VERSION 5.8 ;
BUSBITCHARS "[]" ;
DIVIDERCHAR "/" ;
UNITS
    DATABASE MICRONS 2000 ;
END UNITS

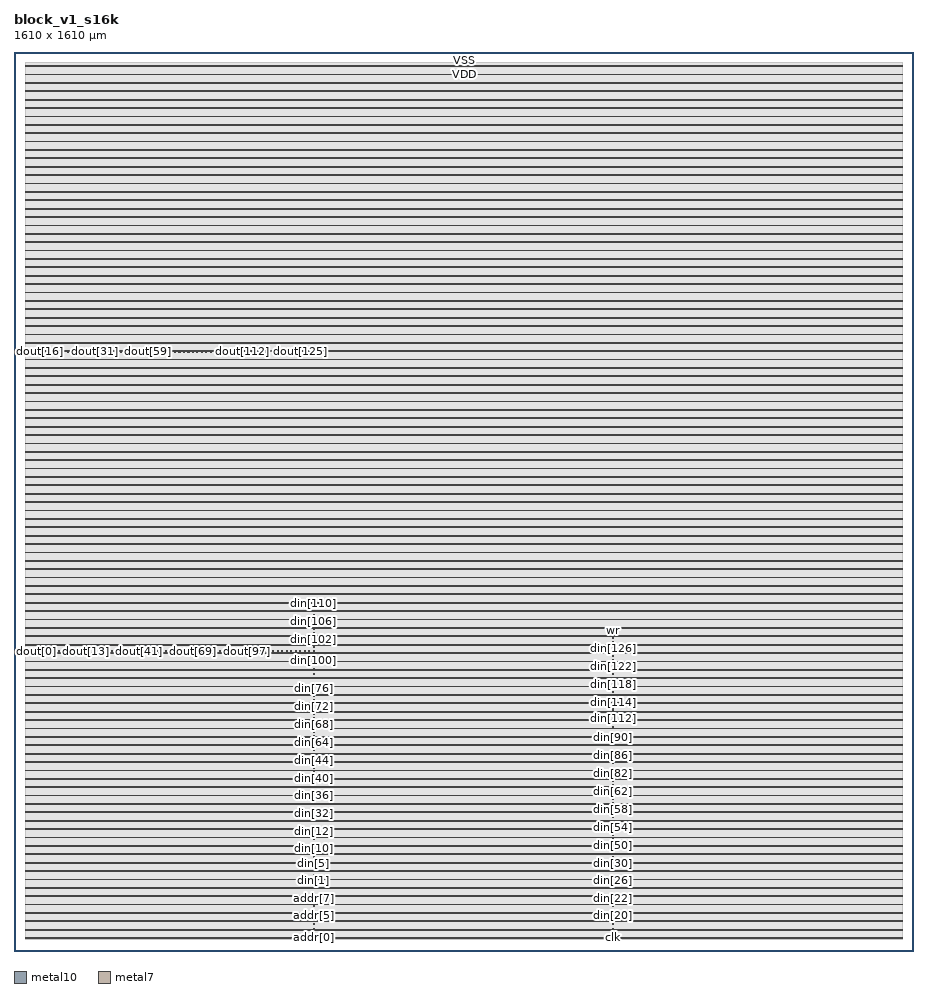
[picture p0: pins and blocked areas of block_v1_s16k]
MACRO block_v1_s16k
  FOREIGN block_v1_s16k 0 0 ;
  CLASS BLOCK ;
  SIZE 1610 BY 1610 ;
  PIN addr[0]
    DIRECTION INPUT ;
    USE SIGNAL ;
    PORT
      LAYER metal10 ;
        RECT  535.095 23.07 537.095 25.07 ;
    END
  END addr[0]
  PIN addr[1]
    DIRECTION INPUT ;
    USE SIGNAL ;
    PORT
      LAYER metal10 ;
        RECT  535.095 31.07 537.095 33.07 ;
    END
  END addr[1]
  PIN addr[2]
    DIRECTION INPUT ;
    USE SIGNAL ;
    PORT
      LAYER metal10 ;
        RECT  535.095 39.07 537.095 41.07 ;
    END
  END addr[2]
  PIN addr[3]
    DIRECTION INPUT ;
    USE SIGNAL ;
    PORT
      LAYER metal10 ;
        RECT  535.095 47.07 537.095 49.07 ;
    END
  END addr[3]
  PIN addr[4]
    DIRECTION INPUT ;
    USE SIGNAL ;
    PORT
      LAYER metal10 ;
        RECT  535.095 55.07 537.095 57.07 ;
    END
  END addr[4]
  PIN addr[5]
    DIRECTION INPUT ;
    USE SIGNAL ;
    PORT
      LAYER metal10 ;
        RECT  535.095 63.07 537.095 65.07 ;
    END
  END addr[5]
  PIN addr[6]
    DIRECTION INPUT ;
    USE SIGNAL ;
    PORT
      LAYER metal10 ;
        RECT  535.095 71.07 537.095 73.07 ;
    END
  END addr[6]
  PIN addr[7]
    DIRECTION INPUT ;
    USE SIGNAL ;
    PORT
      LAYER metal10 ;
        RECT  535.095 79.07 537.095 81.07 ;
    END
  END addr[7]
  PIN addr[8]
    DIRECTION INPUT ;
    USE SIGNAL ;
    PORT
      LAYER metal10 ;
        RECT  535.095 87.07 537.095 89.07 ;
    END
  END addr[8]
  PIN addr[9]
    DIRECTION INPUT ;
    USE SIGNAL ;
    PORT
      LAYER metal10 ;
        RECT  535.095 95.07 537.095 97.07 ;
    END
  END addr[9]
  PIN clk
    DIRECTION INPUT ;
    USE SIGNAL ;
    PORT
      LAYER metal10 ;
        RECT  1071.095 23.07 1073.095 25.07 ;
    END
  END clk
  PIN din[0]
    DIRECTION INPUT ;
    USE SIGNAL ;
    PORT
      LAYER metal10 ;
        RECT  535.095 103.07 537.095 105.07 ;
    END
  END din[0]
  PIN din[100]
    DIRECTION INPUT ;
    USE SIGNAL ;
    PORT
      LAYER metal10 ;
        RECT  535.095 519.07 537.095 521.07 ;
    END
  END din[100]
  PIN din[101]
    DIRECTION INPUT ;
    USE SIGNAL ;
    PORT
      LAYER metal10 ;
        RECT  535.095 527.07 537.095 529.07 ;
    END
  END din[101]
  PIN din[102]
    DIRECTION INPUT ;
    USE SIGNAL ;
    PORT
      LAYER metal10 ;
        RECT  535.095 543.07 537.095 545.07 ;
    END
  END din[102]
  PIN din[103]
    DIRECTION INPUT ;
    USE SIGNAL ;
    PORT
      LAYER metal10 ;
        RECT  535.095 551.07 537.095 553.07 ;
    END
  END din[103]
  PIN din[104]
    DIRECTION INPUT ;
    USE SIGNAL ;
    PORT
      LAYER metal10 ;
        RECT  535.095 559.07 537.095 561.07 ;
    END
  END din[104]
  PIN din[105]
    DIRECTION INPUT ;
    USE SIGNAL ;
    PORT
      LAYER metal10 ;
        RECT  535.095 567.07 537.095 569.07 ;
    END
  END din[105]
  PIN din[106]
    DIRECTION INPUT ;
    USE SIGNAL ;
    PORT
      LAYER metal10 ;
        RECT  535.095 575.07 537.095 577.07 ;
    END
  END din[106]
  PIN din[107]
    DIRECTION INPUT ;
    USE SIGNAL ;
    PORT
      LAYER metal10 ;
        RECT  535.095 583.07 537.095 585.07 ;
    END
  END din[107]
  PIN din[108]
    DIRECTION INPUT ;
    USE SIGNAL ;
    PORT
      LAYER metal10 ;
        RECT  535.095 591.07 537.095 593.07 ;
    END
  END din[108]
  PIN din[109]
    DIRECTION INPUT ;
    USE SIGNAL ;
    PORT
      LAYER metal10 ;
        RECT  535.095 599.07 537.095 601.07 ;
    END
  END din[109]
  PIN din[10]
    DIRECTION INPUT ;
    USE SIGNAL ;
    PORT
      LAYER metal10 ;
        RECT  535.095 183.07 537.095 185.07 ;
    END
  END din[10]
  PIN din[110]
    DIRECTION INPUT ;
    USE SIGNAL ;
    PORT
      LAYER metal10 ;
        RECT  535.095 607.07 537.095 609.07 ;
    END
  END din[110]
  PIN din[111]
    DIRECTION INPUT ;
    USE SIGNAL ;
    PORT
      LAYER metal10 ;
        RECT  535.095 615.07 537.095 617.07 ;
    END
  END din[111]
  PIN din[112]
    DIRECTION INPUT ;
    USE SIGNAL ;
    PORT
      LAYER metal10 ;
        RECT  1071.095 415.07 1073.095 417.07 ;
    END
  END din[112]
  PIN din[113]
    DIRECTION INPUT ;
    USE SIGNAL ;
    PORT
      LAYER metal10 ;
        RECT  1071.095 423.07 1073.095 425.07 ;
    END
  END din[113]
  PIN din[114]
    DIRECTION INPUT ;
    USE SIGNAL ;
    PORT
      LAYER metal10 ;
        RECT  1071.095 431.07 1073.095 433.07 ;
    END
  END din[114]
  PIN din[115]
    DIRECTION INPUT ;
    USE SIGNAL ;
    PORT
      LAYER metal10 ;
        RECT  1071.095 439.07 1073.095 441.07 ;
    END
  END din[115]
  PIN din[116]
    DIRECTION INPUT ;
    USE SIGNAL ;
    PORT
      LAYER metal10 ;
        RECT  1071.095 447.07 1073.095 449.07 ;
    END
  END din[116]
  PIN din[117]
    DIRECTION INPUT ;
    USE SIGNAL ;
    PORT
      LAYER metal10 ;
        RECT  1071.095 455.07 1073.095 457.07 ;
    END
  END din[117]
  PIN din[118]
    DIRECTION INPUT ;
    USE SIGNAL ;
    PORT
      LAYER metal10 ;
        RECT  1071.095 463.07 1073.095 465.07 ;
    END
  END din[118]
  PIN din[119]
    DIRECTION INPUT ;
    USE SIGNAL ;
    PORT
      LAYER metal10 ;
        RECT  1071.095 471.07 1073.095 473.07 ;
    END
  END din[119]
  PIN din[11]
    DIRECTION INPUT ;
    USE SIGNAL ;
    PORT
      LAYER metal10 ;
        RECT  535.095 191.07 537.095 193.07 ;
    END
  END din[11]
  PIN din[120]
    DIRECTION INPUT ;
    USE SIGNAL ;
    PORT
      LAYER metal10 ;
        RECT  1071.095 479.07 1073.095 481.07 ;
    END
  END din[120]
  PIN din[121]
    DIRECTION INPUT ;
    USE SIGNAL ;
    PORT
      LAYER metal10 ;
        RECT  1071.095 487.07 1073.095 489.07 ;
    END
  END din[121]
  PIN din[122]
    DIRECTION INPUT ;
    USE SIGNAL ;
    PORT
      LAYER metal10 ;
        RECT  1071.095 495.07 1073.095 497.07 ;
    END
  END din[122]
  PIN din[123]
    DIRECTION INPUT ;
    USE SIGNAL ;
    PORT
      LAYER metal10 ;
        RECT  1071.095 503.07 1073.095 505.07 ;
    END
  END din[123]
  PIN din[124]
    DIRECTION INPUT ;
    USE SIGNAL ;
    PORT
      LAYER metal10 ;
        RECT  1071.095 511.07 1073.095 513.07 ;
    END
  END din[124]
  PIN din[125]
    DIRECTION INPUT ;
    USE SIGNAL ;
    PORT
      LAYER metal10 ;
        RECT  1071.095 519.07 1073.095 521.07 ;
    END
  END din[125]
  PIN din[126]
    DIRECTION INPUT ;
    USE SIGNAL ;
    PORT
      LAYER metal10 ;
        RECT  1071.095 527.07 1073.095 529.07 ;
    END
  END din[126]
  PIN din[127]
    DIRECTION INPUT ;
    USE SIGNAL ;
    PORT
      LAYER metal10 ;
        RECT  1071.095 543.07 1073.095 545.07 ;
    END
  END din[127]
  PIN din[12]
    DIRECTION INPUT ;
    USE SIGNAL ;
    PORT
      LAYER metal10 ;
        RECT  535.095 199.07 537.095 201.07 ;
    END
  END din[12]
  PIN din[13]
    DIRECTION INPUT ;
    USE SIGNAL ;
    PORT
      LAYER metal10 ;
        RECT  535.095 207.07 537.095 209.07 ;
    END
  END din[13]
  PIN din[14]
    DIRECTION INPUT ;
    USE SIGNAL ;
    PORT
      LAYER metal10 ;
        RECT  535.095 215.07 537.095 217.07 ;
    END
  END din[14]
  PIN din[15]
    DIRECTION INPUT ;
    USE SIGNAL ;
    PORT
      LAYER metal10 ;
        RECT  535.095 223.07 537.095 225.07 ;
    END
  END din[15]
  PIN din[16]
    DIRECTION INPUT ;
    USE SIGNAL ;
    PORT
      LAYER metal10 ;
        RECT  1071.095 31.07 1073.095 33.07 ;
    END
  END din[16]
  PIN din[17]
    DIRECTION INPUT ;
    USE SIGNAL ;
    PORT
      LAYER metal10 ;
        RECT  1071.095 39.07 1073.095 41.07 ;
    END
  END din[17]
  PIN din[18]
    DIRECTION INPUT ;
    USE SIGNAL ;
    PORT
      LAYER metal10 ;
        RECT  1071.095 47.07 1073.095 49.07 ;
    END
  END din[18]
  PIN din[19]
    DIRECTION INPUT ;
    USE SIGNAL ;
    PORT
      LAYER metal10 ;
        RECT  1071.095 55.07 1073.095 57.07 ;
    END
  END din[19]
  PIN din[1]
    DIRECTION INPUT ;
    USE SIGNAL ;
    PORT
      LAYER metal10 ;
        RECT  535.095 111.07 537.095 113.07 ;
    END
  END din[1]
  PIN din[20]
    DIRECTION INPUT ;
    USE SIGNAL ;
    PORT
      LAYER metal10 ;
        RECT  1071.095 63.07 1073.095 65.07 ;
    END
  END din[20]
  PIN din[21]
    DIRECTION INPUT ;
    USE SIGNAL ;
    PORT
      LAYER metal10 ;
        RECT  1071.095 71.07 1073.095 73.07 ;
    END
  END din[21]
  PIN din[22]
    DIRECTION INPUT ;
    USE SIGNAL ;
    PORT
      LAYER metal10 ;
        RECT  1071.095 79.07 1073.095 81.07 ;
    END
  END din[22]
  PIN din[23]
    DIRECTION INPUT ;
    USE SIGNAL ;
    PORT
      LAYER metal10 ;
        RECT  1071.095 87.07 1073.095 89.07 ;
    END
  END din[23]
  PIN din[24]
    DIRECTION INPUT ;
    USE SIGNAL ;
    PORT
      LAYER metal10 ;
        RECT  1071.095 95.07 1073.095 97.07 ;
    END
  END din[24]
  PIN din[25]
    DIRECTION INPUT ;
    USE SIGNAL ;
    PORT
      LAYER metal10 ;
        RECT  1071.095 103.07 1073.095 105.07 ;
    END
  END din[25]
  PIN din[26]
    DIRECTION INPUT ;
    USE SIGNAL ;
    PORT
      LAYER metal10 ;
        RECT  1071.095 111.07 1073.095 113.07 ;
    END
  END din[26]
  PIN din[27]
    DIRECTION INPUT ;
    USE SIGNAL ;
    PORT
      LAYER metal10 ;
        RECT  1071.095 119.07 1073.095 121.07 ;
    END
  END din[27]
  PIN din[28]
    DIRECTION INPUT ;
    USE SIGNAL ;
    PORT
      LAYER metal10 ;
        RECT  1071.095 127.07 1073.095 129.07 ;
    END
  END din[28]
  PIN din[29]
    DIRECTION INPUT ;
    USE SIGNAL ;
    PORT
      LAYER metal10 ;
        RECT  1071.095 135.07 1073.095 137.07 ;
    END
  END din[29]
  PIN din[2]
    DIRECTION INPUT ;
    USE SIGNAL ;
    PORT
      LAYER metal10 ;
        RECT  535.095 119.07 537.095 121.07 ;
    END
  END din[2]
  PIN din[30]
    DIRECTION INPUT ;
    USE SIGNAL ;
    PORT
      LAYER metal10 ;
        RECT  1071.095 143.07 1073.095 145.07 ;
    END
  END din[30]
  PIN din[31]
    DIRECTION INPUT ;
    USE SIGNAL ;
    PORT
      LAYER metal10 ;
        RECT  1071.095 151.07 1073.095 153.07 ;
    END
  END din[31]
  PIN din[32]
    DIRECTION INPUT ;
    USE SIGNAL ;
    PORT
      LAYER metal10 ;
        RECT  535.095 231.07 537.095 233.07 ;
    END
  END din[32]
  PIN din[33]
    DIRECTION INPUT ;
    USE SIGNAL ;
    PORT
      LAYER metal10 ;
        RECT  535.095 239.07 537.095 241.07 ;
    END
  END din[33]
  PIN din[34]
    DIRECTION INPUT ;
    USE SIGNAL ;
    PORT
      LAYER metal10 ;
        RECT  535.095 247.07 537.095 249.07 ;
    END
  END din[34]
  PIN din[35]
    DIRECTION INPUT ;
    USE SIGNAL ;
    PORT
      LAYER metal10 ;
        RECT  535.095 255.07 537.095 257.07 ;
    END
  END din[35]
  PIN din[36]
    DIRECTION INPUT ;
    USE SIGNAL ;
    PORT
      LAYER metal10 ;
        RECT  535.095 263.07 537.095 265.07 ;
    END
  END din[36]
  PIN din[37]
    DIRECTION INPUT ;
    USE SIGNAL ;
    PORT
      LAYER metal10 ;
        RECT  535.095 271.07 537.095 273.07 ;
    END
  END din[37]
  PIN din[38]
    DIRECTION INPUT ;
    USE SIGNAL ;
    PORT
      LAYER metal10 ;
        RECT  535.095 279.07 537.095 281.07 ;
    END
  END din[38]
  PIN din[39]
    DIRECTION INPUT ;
    USE SIGNAL ;
    PORT
      LAYER metal10 ;
        RECT  535.095 287.07 537.095 289.07 ;
    END
  END din[39]
  PIN din[3]
    DIRECTION INPUT ;
    USE SIGNAL ;
    PORT
      LAYER metal10 ;
        RECT  535.095 127.07 537.095 129.07 ;
    END
  END din[3]
  PIN din[40]
    DIRECTION INPUT ;
    USE SIGNAL ;
    PORT
      LAYER metal10 ;
        RECT  535.095 295.07 537.095 297.07 ;
    END
  END din[40]
  PIN din[41]
    DIRECTION INPUT ;
    USE SIGNAL ;
    PORT
      LAYER metal10 ;
        RECT  535.095 303.07 537.095 305.07 ;
    END
  END din[41]
  PIN din[42]
    DIRECTION INPUT ;
    USE SIGNAL ;
    PORT
      LAYER metal10 ;
        RECT  535.095 311.07 537.095 313.07 ;
    END
  END din[42]
  PIN din[43]
    DIRECTION INPUT ;
    USE SIGNAL ;
    PORT
      LAYER metal10 ;
        RECT  535.095 319.07 537.095 321.07 ;
    END
  END din[43]
  PIN din[44]
    DIRECTION INPUT ;
    USE SIGNAL ;
    PORT
      LAYER metal10 ;
        RECT  535.095 327.07 537.095 329.07 ;
    END
  END din[44]
  PIN din[45]
    DIRECTION INPUT ;
    USE SIGNAL ;
    PORT
      LAYER metal10 ;
        RECT  535.095 335.07 537.095 337.07 ;
    END
  END din[45]
  PIN din[46]
    DIRECTION INPUT ;
    USE SIGNAL ;
    PORT
      LAYER metal10 ;
        RECT  535.095 343.07 537.095 345.07 ;
    END
  END din[46]
  PIN din[47]
    DIRECTION INPUT ;
    USE SIGNAL ;
    PORT
      LAYER metal10 ;
        RECT  535.095 351.07 537.095 353.07 ;
    END
  END din[47]
  PIN din[48]
    DIRECTION INPUT ;
    USE SIGNAL ;
    PORT
      LAYER metal10 ;
        RECT  1071.095 159.07 1073.095 161.07 ;
    END
  END din[48]
  PIN din[49]
    DIRECTION INPUT ;
    USE SIGNAL ;
    PORT
      LAYER metal10 ;
        RECT  1071.095 167.07 1073.095 169.07 ;
    END
  END din[49]
  PIN din[4]
    DIRECTION INPUT ;
    USE SIGNAL ;
    PORT
      LAYER metal10 ;
        RECT  535.095 135.07 537.095 137.07 ;
    END
  END din[4]
  PIN din[50]
    DIRECTION INPUT ;
    USE SIGNAL ;
    PORT
      LAYER metal10 ;
        RECT  1071.095 175.07 1073.095 177.07 ;
    END
  END din[50]
  PIN din[51]
    DIRECTION INPUT ;
    USE SIGNAL ;
    PORT
      LAYER metal10 ;
        RECT  1071.095 183.07 1073.095 185.07 ;
    END
  END din[51]
  PIN din[52]
    DIRECTION INPUT ;
    USE SIGNAL ;
    PORT
      LAYER metal10 ;
        RECT  1071.095 191.07 1073.095 193.07 ;
    END
  END din[52]
  PIN din[53]
    DIRECTION INPUT ;
    USE SIGNAL ;
    PORT
      LAYER metal10 ;
        RECT  1071.095 199.07 1073.095 201.07 ;
    END
  END din[53]
  PIN din[54]
    DIRECTION INPUT ;
    USE SIGNAL ;
    PORT
      LAYER metal10 ;
        RECT  1071.095 207.07 1073.095 209.07 ;
    END
  END din[54]
  PIN din[55]
    DIRECTION INPUT ;
    USE SIGNAL ;
    PORT
      LAYER metal10 ;
        RECT  1071.095 215.07 1073.095 217.07 ;
    END
  END din[55]
  PIN din[56]
    DIRECTION INPUT ;
    USE SIGNAL ;
    PORT
      LAYER metal10 ;
        RECT  1071.095 223.07 1073.095 225.07 ;
    END
  END din[56]
  PIN din[57]
    DIRECTION INPUT ;
    USE SIGNAL ;
    PORT
      LAYER metal10 ;
        RECT  1071.095 231.07 1073.095 233.07 ;
    END
  END din[57]
  PIN din[58]
    DIRECTION INPUT ;
    USE SIGNAL ;
    PORT
      LAYER metal10 ;
        RECT  1071.095 239.07 1073.095 241.07 ;
    END
  END din[58]
  PIN din[59]
    DIRECTION INPUT ;
    USE SIGNAL ;
    PORT
      LAYER metal10 ;
        RECT  1071.095 247.07 1073.095 249.07 ;
    END
  END din[59]
  PIN din[5]
    DIRECTION INPUT ;
    USE SIGNAL ;
    PORT
      LAYER metal10 ;
        RECT  535.095 143.07 537.095 145.07 ;
    END
  END din[5]
  PIN din[60]
    DIRECTION INPUT ;
    USE SIGNAL ;
    PORT
      LAYER metal10 ;
        RECT  1071.095 255.07 1073.095 257.07 ;
    END
  END din[60]
  PIN din[61]
    DIRECTION INPUT ;
    USE SIGNAL ;
    PORT
      LAYER metal10 ;
        RECT  1071.095 263.07 1073.095 265.07 ;
    END
  END din[61]
  PIN din[62]
    DIRECTION INPUT ;
    USE SIGNAL ;
    PORT
      LAYER metal10 ;
        RECT  1071.095 271.07 1073.095 273.07 ;
    END
  END din[62]
  PIN din[63]
    DIRECTION INPUT ;
    USE SIGNAL ;
    PORT
      LAYER metal10 ;
        RECT  1071.095 279.07 1073.095 281.07 ;
    END
  END din[63]
  PIN din[64]
    DIRECTION INPUT ;
    USE SIGNAL ;
    PORT
      LAYER metal10 ;
        RECT  535.095 359.07 537.095 361.07 ;
    END
  END din[64]
  PIN din[65]
    DIRECTION INPUT ;
    USE SIGNAL ;
    PORT
      LAYER metal10 ;
        RECT  535.095 367.07 537.095 369.07 ;
    END
  END din[65]
  PIN din[66]
    DIRECTION INPUT ;
    USE SIGNAL ;
    PORT
      LAYER metal10 ;
        RECT  535.095 375.07 537.095 377.07 ;
    END
  END din[66]
  PIN din[67]
    DIRECTION INPUT ;
    USE SIGNAL ;
    PORT
      LAYER metal10 ;
        RECT  535.095 383.07 537.095 385.07 ;
    END
  END din[67]
  PIN din[68]
    DIRECTION INPUT ;
    USE SIGNAL ;
    PORT
      LAYER metal10 ;
        RECT  535.095 391.07 537.095 393.07 ;
    END
  END din[68]
  PIN din[69]
    DIRECTION INPUT ;
    USE SIGNAL ;
    PORT
      LAYER metal10 ;
        RECT  535.095 399.07 537.095 401.07 ;
    END
  END din[69]
  PIN din[6]
    DIRECTION INPUT ;
    USE SIGNAL ;
    PORT
      LAYER metal10 ;
        RECT  535.095 151.07 537.095 153.07 ;
    END
  END din[6]
  PIN din[70]
    DIRECTION INPUT ;
    USE SIGNAL ;
    PORT
      LAYER metal10 ;
        RECT  535.095 407.07 537.095 409.07 ;
    END
  END din[70]
  PIN din[71]
    DIRECTION INPUT ;
    USE SIGNAL ;
    PORT
      LAYER metal10 ;
        RECT  535.095 415.07 537.095 417.07 ;
    END
  END din[71]
  PIN din[72]
    DIRECTION INPUT ;
    USE SIGNAL ;
    PORT
      LAYER metal10 ;
        RECT  535.095 423.07 537.095 425.07 ;
    END
  END din[72]
  PIN din[73]
    DIRECTION INPUT ;
    USE SIGNAL ;
    PORT
      LAYER metal10 ;
        RECT  535.095 431.07 537.095 433.07 ;
    END
  END din[73]
  PIN din[74]
    DIRECTION INPUT ;
    USE SIGNAL ;
    PORT
      LAYER metal10 ;
        RECT  535.095 439.07 537.095 441.07 ;
    END
  END din[74]
  PIN din[75]
    DIRECTION INPUT ;
    USE SIGNAL ;
    PORT
      LAYER metal10 ;
        RECT  535.095 447.07 537.095 449.07 ;
    END
  END din[75]
  PIN din[76]
    DIRECTION INPUT ;
    USE SIGNAL ;
    PORT
      LAYER metal10 ;
        RECT  535.095 455.07 537.095 457.07 ;
    END
  END din[76]
  PIN din[77]
    DIRECTION INPUT ;
    USE SIGNAL ;
    PORT
      LAYER metal10 ;
        RECT  535.095 463.07 537.095 465.07 ;
    END
  END din[77]
  PIN din[78]
    DIRECTION INPUT ;
    USE SIGNAL ;
    PORT
      LAYER metal10 ;
        RECT  535.095 471.07 537.095 473.07 ;
    END
  END din[78]
  PIN din[79]
    DIRECTION INPUT ;
    USE SIGNAL ;
    PORT
      LAYER metal10 ;
        RECT  535.095 479.07 537.095 481.07 ;
    END
  END din[79]
  PIN din[7]
    DIRECTION INPUT ;
    USE SIGNAL ;
    PORT
      LAYER metal10 ;
        RECT  535.095 159.07 537.095 161.07 ;
    END
  END din[7]
  PIN din[80]
    DIRECTION INPUT ;
    USE SIGNAL ;
    PORT
      LAYER metal10 ;
        RECT  1071.095 287.07 1073.095 289.07 ;
    END
  END din[80]
  PIN din[81]
    DIRECTION INPUT ;
    USE SIGNAL ;
    PORT
      LAYER metal10 ;
        RECT  1071.095 295.07 1073.095 297.07 ;
    END
  END din[81]
  PIN din[82]
    DIRECTION INPUT ;
    USE SIGNAL ;
    PORT
      LAYER metal10 ;
        RECT  1071.095 303.07 1073.095 305.07 ;
    END
  END din[82]
  PIN din[83]
    DIRECTION INPUT ;
    USE SIGNAL ;
    PORT
      LAYER metal10 ;
        RECT  1071.095 311.07 1073.095 313.07 ;
    END
  END din[83]
  PIN din[84]
    DIRECTION INPUT ;
    USE SIGNAL ;
    PORT
      LAYER metal10 ;
        RECT  1071.095 319.07 1073.095 321.07 ;
    END
  END din[84]
  PIN din[85]
    DIRECTION INPUT ;
    USE SIGNAL ;
    PORT
      LAYER metal10 ;
        RECT  1071.095 327.07 1073.095 329.07 ;
    END
  END din[85]
  PIN din[86]
    DIRECTION INPUT ;
    USE SIGNAL ;
    PORT
      LAYER metal10 ;
        RECT  1071.095 335.07 1073.095 337.07 ;
    END
  END din[86]
  PIN din[87]
    DIRECTION INPUT ;
    USE SIGNAL ;
    PORT
      LAYER metal10 ;
        RECT  1071.095 343.07 1073.095 345.07 ;
    END
  END din[87]
  PIN din[88]
    DIRECTION INPUT ;
    USE SIGNAL ;
    PORT
      LAYER metal10 ;
        RECT  1071.095 351.07 1073.095 353.07 ;
    END
  END din[88]
  PIN din[89]
    DIRECTION INPUT ;
    USE SIGNAL ;
    PORT
      LAYER metal10 ;
        RECT  1071.095 359.07 1073.095 361.07 ;
    END
  END din[89]
  PIN din[8]
    DIRECTION INPUT ;
    USE SIGNAL ;
    PORT
      LAYER metal10 ;
        RECT  535.095 167.07 537.095 169.07 ;
    END
  END din[8]
  PIN din[90]
    DIRECTION INPUT ;
    USE SIGNAL ;
    PORT
      LAYER metal10 ;
        RECT  1071.095 367.07 1073.095 369.07 ;
    END
  END din[90]
  PIN din[91]
    DIRECTION INPUT ;
    USE SIGNAL ;
    PORT
      LAYER metal10 ;
        RECT  1071.095 375.07 1073.095 377.07 ;
    END
  END din[91]
  PIN din[92]
    DIRECTION INPUT ;
    USE SIGNAL ;
    PORT
      LAYER metal10 ;
        RECT  1071.095 383.07 1073.095 385.07 ;
    END
  END din[92]
  PIN din[93]
    DIRECTION INPUT ;
    USE SIGNAL ;
    PORT
      LAYER metal10 ;
        RECT  1071.095 391.07 1073.095 393.07 ;
    END
  END din[93]
  PIN din[94]
    DIRECTION INPUT ;
    USE SIGNAL ;
    PORT
      LAYER metal10 ;
        RECT  1071.095 399.07 1073.095 401.07 ;
    END
  END din[94]
  PIN din[95]
    DIRECTION INPUT ;
    USE SIGNAL ;
    PORT
      LAYER metal10 ;
        RECT  1071.095 407.07 1073.095 409.07 ;
    END
  END din[95]
  PIN din[96]
    DIRECTION INPUT ;
    USE SIGNAL ;
    PORT
      LAYER metal10 ;
        RECT  535.095 487.07 537.095 489.07 ;
    END
  END din[96]
  PIN din[97]
    DIRECTION INPUT ;
    USE SIGNAL ;
    PORT
      LAYER metal10 ;
        RECT  535.095 495.07 537.095 497.07 ;
    END
  END din[97]
  PIN din[98]
    DIRECTION INPUT ;
    USE SIGNAL ;
    PORT
      LAYER metal10 ;
        RECT  535.095 503.07 537.095 505.07 ;
    END
  END din[98]
  PIN din[99]
    DIRECTION INPUT ;
    USE SIGNAL ;
    PORT
      LAYER metal10 ;
        RECT  535.095 511.07 537.095 513.07 ;
    END
  END din[99]
  PIN din[9]
    DIRECTION INPUT ;
    USE SIGNAL ;
    PORT
      LAYER metal10 ;
        RECT  535.095 175.07 537.095 177.07 ;
    END
  END din[9]
  PIN dout[0]
    DIRECTION OUTPUT ;
    USE SIGNAL ;
    PORT
      LAYER metal10 ;
        RECT  23.095 535.07 25.095 537.07 ;
    END
  END dout[0]
  PIN dout[100]
    DIRECTION OUTPUT ;
    USE SIGNAL ;
    PORT
      LAYER metal10 ;
        RECT  439.095 535.07 441.095 537.07 ;
    END
  END dout[100]
  PIN dout[101]
    DIRECTION OUTPUT ;
    USE SIGNAL ;
    PORT
      LAYER metal10 ;
        RECT  447.095 535.07 449.095 537.07 ;
    END
  END dout[101]
  PIN dout[102]
    DIRECTION OUTPUT ;
    USE SIGNAL ;
    PORT
      LAYER metal10 ;
        RECT  455.095 535.07 457.095 537.07 ;
    END
  END dout[102]
  PIN dout[103]
    DIRECTION OUTPUT ;
    USE SIGNAL ;
    PORT
      LAYER metal10 ;
        RECT  463.095 535.07 465.095 537.07 ;
    END
  END dout[103]
  PIN dout[104]
    DIRECTION OUTPUT ;
    USE SIGNAL ;
    PORT
      LAYER metal10 ;
        RECT  471.095 535.07 473.095 537.07 ;
    END
  END dout[104]
  PIN dout[105]
    DIRECTION OUTPUT ;
    USE SIGNAL ;
    PORT
      LAYER metal10 ;
        RECT  479.095 535.07 481.095 537.07 ;
    END
  END dout[105]
  PIN dout[106]
    DIRECTION OUTPUT ;
    USE SIGNAL ;
    PORT
      LAYER metal10 ;
        RECT  487.095 535.07 489.095 537.07 ;
    END
  END dout[106]
  PIN dout[107]
    DIRECTION OUTPUT ;
    USE SIGNAL ;
    PORT
      LAYER metal10 ;
        RECT  495.095 535.07 497.095 537.07 ;
    END
  END dout[107]
  PIN dout[108]
    DIRECTION OUTPUT ;
    USE SIGNAL ;
    PORT
      LAYER metal10 ;
        RECT  503.095 535.07 505.095 537.07 ;
    END
  END dout[108]
  PIN dout[109]
    DIRECTION OUTPUT ;
    USE SIGNAL ;
    PORT
      LAYER metal10 ;
        RECT  511.095 535.07 513.095 537.07 ;
    END
  END dout[109]
  PIN dout[10]
    DIRECTION OUTPUT ;
    USE SIGNAL ;
    PORT
      LAYER metal10 ;
        RECT  103.095 535.07 105.095 537.07 ;
    END
  END dout[10]
  PIN dout[110]
    DIRECTION OUTPUT ;
    USE SIGNAL ;
    PORT
      LAYER metal10 ;
        RECT  519.095 535.07 521.095 537.07 ;
    END
  END dout[110]
  PIN dout[111]
    DIRECTION OUTPUT ;
    USE SIGNAL ;
    PORT
      LAYER metal10 ;
        RECT  527.095 535.07 529.095 537.07 ;
    END
  END dout[111]
  PIN dout[112]
    DIRECTION OUTPUT ;
    USE SIGNAL ;
    PORT
      LAYER metal10 ;
        RECT  407.095 1071.07 409.095 1073.07 ;
    END
  END dout[112]
  PIN dout[113]
    DIRECTION OUTPUT ;
    USE SIGNAL ;
    PORT
      LAYER metal10 ;
        RECT  415.095 1071.07 417.095 1073.07 ;
    END
  END dout[113]
  PIN dout[114]
    DIRECTION OUTPUT ;
    USE SIGNAL ;
    PORT
      LAYER metal10 ;
        RECT  423.095 1071.07 425.095 1073.07 ;
    END
  END dout[114]
  PIN dout[115]
    DIRECTION OUTPUT ;
    USE SIGNAL ;
    PORT
      LAYER metal10 ;
        RECT  431.095 1071.07 433.095 1073.07 ;
    END
  END dout[115]
  PIN dout[116]
    DIRECTION OUTPUT ;
    USE SIGNAL ;
    PORT
      LAYER metal10 ;
        RECT  439.095 1071.07 441.095 1073.07 ;
    END
  END dout[116]
  PIN dout[117]
    DIRECTION OUTPUT ;
    USE SIGNAL ;
    PORT
      LAYER metal10 ;
        RECT  447.095 1071.07 449.095 1073.07 ;
    END
  END dout[117]
  PIN dout[118]
    DIRECTION OUTPUT ;
    USE SIGNAL ;
    PORT
      LAYER metal10 ;
        RECT  455.095 1071.07 457.095 1073.07 ;
    END
  END dout[118]
  PIN dout[119]
    DIRECTION OUTPUT ;
    USE SIGNAL ;
    PORT
      LAYER metal10 ;
        RECT  463.095 1071.07 465.095 1073.07 ;
    END
  END dout[119]
  PIN dout[11]
    DIRECTION OUTPUT ;
    USE SIGNAL ;
    PORT
      LAYER metal10 ;
        RECT  111.095 535.07 113.095 537.07 ;
    END
  END dout[11]
  PIN dout[120]
    DIRECTION OUTPUT ;
    USE SIGNAL ;
    PORT
      LAYER metal10 ;
        RECT  471.095 1071.07 473.095 1073.07 ;
    END
  END dout[120]
  PIN dout[121]
    DIRECTION OUTPUT ;
    USE SIGNAL ;
    PORT
      LAYER metal10 ;
        RECT  479.095 1071.07 481.095 1073.07 ;
    END
  END dout[121]
  PIN dout[122]
    DIRECTION OUTPUT ;
    USE SIGNAL ;
    PORT
      LAYER metal10 ;
        RECT  487.095 1071.07 489.095 1073.07 ;
    END
  END dout[122]
  PIN dout[123]
    DIRECTION OUTPUT ;
    USE SIGNAL ;
    PORT
      LAYER metal10 ;
        RECT  495.095 1071.07 497.095 1073.07 ;
    END
  END dout[123]
  PIN dout[124]
    DIRECTION OUTPUT ;
    USE SIGNAL ;
    PORT
      LAYER metal10 ;
        RECT  503.095 1071.07 505.095 1073.07 ;
    END
  END dout[124]
  PIN dout[125]
    DIRECTION OUTPUT ;
    USE SIGNAL ;
    PORT
      LAYER metal10 ;
        RECT  511.095 1071.07 513.095 1073.07 ;
    END
  END dout[125]
  PIN dout[126]
    DIRECTION OUTPUT ;
    USE SIGNAL ;
    PORT
      LAYER metal10 ;
        RECT  519.095 1071.07 521.095 1073.07 ;
    END
  END dout[126]
  PIN dout[127]
    DIRECTION OUTPUT ;
    USE SIGNAL ;
    PORT
      LAYER metal10 ;
        RECT  527.095 1071.07 529.095 1073.07 ;
    END
  END dout[127]
  PIN dout[12]
    DIRECTION OUTPUT ;
    USE SIGNAL ;
    PORT
      LAYER metal10 ;
        RECT  119.095 535.07 121.095 537.07 ;
    END
  END dout[12]
  PIN dout[13]
    DIRECTION OUTPUT ;
    USE SIGNAL ;
    PORT
      LAYER metal10 ;
        RECT  127.095 535.07 129.095 537.07 ;
    END
  END dout[13]
  PIN dout[14]
    DIRECTION OUTPUT ;
    USE SIGNAL ;
    PORT
      LAYER metal10 ;
        RECT  135.095 535.07 137.095 537.07 ;
    END
  END dout[14]
  PIN dout[15]
    DIRECTION OUTPUT ;
    USE SIGNAL ;
    PORT
      LAYER metal10 ;
        RECT  143.095 535.07 145.095 537.07 ;
    END
  END dout[15]
  PIN dout[16]
    DIRECTION OUTPUT ;
    USE SIGNAL ;
    PORT
      LAYER metal10 ;
        RECT  23.095 1071.07 25.095 1073.07 ;
    END
  END dout[16]
  PIN dout[17]
    DIRECTION OUTPUT ;
    USE SIGNAL ;
    PORT
      LAYER metal10 ;
        RECT  31.095 1071.07 33.095 1073.07 ;
    END
  END dout[17]
  PIN dout[18]
    DIRECTION OUTPUT ;
    USE SIGNAL ;
    PORT
      LAYER metal10 ;
        RECT  39.095 1071.07 41.095 1073.07 ;
    END
  END dout[18]
  PIN dout[19]
    DIRECTION OUTPUT ;
    USE SIGNAL ;
    PORT
      LAYER metal10 ;
        RECT  47.095 1071.07 49.095 1073.07 ;
    END
  END dout[19]
  PIN dout[1]
    DIRECTION OUTPUT ;
    USE SIGNAL ;
    PORT
      LAYER metal10 ;
        RECT  31.095 535.07 33.095 537.07 ;
    END
  END dout[1]
  PIN dout[20]
    DIRECTION OUTPUT ;
    USE SIGNAL ;
    PORT
      LAYER metal10 ;
        RECT  55.095 1071.07 57.095 1073.07 ;
    END
  END dout[20]
  PIN dout[21]
    DIRECTION OUTPUT ;
    USE SIGNAL ;
    PORT
      LAYER metal10 ;
        RECT  63.095 1071.07 65.095 1073.07 ;
    END
  END dout[21]
  PIN dout[22]
    DIRECTION OUTPUT ;
    USE SIGNAL ;
    PORT
      LAYER metal10 ;
        RECT  71.095 1071.07 73.095 1073.07 ;
    END
  END dout[22]
  PIN dout[23]
    DIRECTION OUTPUT ;
    USE SIGNAL ;
    PORT
      LAYER metal10 ;
        RECT  79.095 1071.07 81.095 1073.07 ;
    END
  END dout[23]
  PIN dout[24]
    DIRECTION OUTPUT ;
    USE SIGNAL ;
    PORT
      LAYER metal10 ;
        RECT  87.095 1071.07 89.095 1073.07 ;
    END
  END dout[24]
  PIN dout[25]
    DIRECTION OUTPUT ;
    USE SIGNAL ;
    PORT
      LAYER metal10 ;
        RECT  95.095 1071.07 97.095 1073.07 ;
    END
  END dout[25]
  PIN dout[26]
    DIRECTION OUTPUT ;
    USE SIGNAL ;
    PORT
      LAYER metal10 ;
        RECT  103.095 1071.07 105.095 1073.07 ;
    END
  END dout[26]
  PIN dout[27]
    DIRECTION OUTPUT ;
    USE SIGNAL ;
    PORT
      LAYER metal10 ;
        RECT  111.095 1071.07 113.095 1073.07 ;
    END
  END dout[27]
  PIN dout[28]
    DIRECTION OUTPUT ;
    USE SIGNAL ;
    PORT
      LAYER metal10 ;
        RECT  119.095 1071.07 121.095 1073.07 ;
    END
  END dout[28]
  PIN dout[29]
    DIRECTION OUTPUT ;
    USE SIGNAL ;
    PORT
      LAYER metal10 ;
        RECT  127.095 1071.07 129.095 1073.07 ;
    END
  END dout[29]
  PIN dout[2]
    DIRECTION OUTPUT ;
    USE SIGNAL ;
    PORT
      LAYER metal10 ;
        RECT  39.095 535.07 41.095 537.07 ;
    END
  END dout[2]
  PIN dout[30]
    DIRECTION OUTPUT ;
    USE SIGNAL ;
    PORT
      LAYER metal10 ;
        RECT  135.095 1071.07 137.095 1073.07 ;
    END
  END dout[30]
  PIN dout[31]
    DIRECTION OUTPUT ;
    USE SIGNAL ;
    PORT
      LAYER metal10 ;
        RECT  143.095 1071.07 145.095 1073.07 ;
    END
  END dout[31]
  PIN dout[32]
    DIRECTION OUTPUT ;
    USE SIGNAL ;
    PORT
      LAYER metal10 ;
        RECT  151.095 535.07 153.095 537.07 ;
    END
  END dout[32]
  PIN dout[33]
    DIRECTION OUTPUT ;
    USE SIGNAL ;
    PORT
      LAYER metal10 ;
        RECT  159.095 535.07 161.095 537.07 ;
    END
  END dout[33]
  PIN dout[34]
    DIRECTION OUTPUT ;
    USE SIGNAL ;
    PORT
      LAYER metal10 ;
        RECT  167.095 535.07 169.095 537.07 ;
    END
  END dout[34]
  PIN dout[35]
    DIRECTION OUTPUT ;
    USE SIGNAL ;
    PORT
      LAYER metal10 ;
        RECT  175.095 535.07 177.095 537.07 ;
    END
  END dout[35]
  PIN dout[36]
    DIRECTION OUTPUT ;
    USE SIGNAL ;
    PORT
      LAYER metal10 ;
        RECT  183.095 535.07 185.095 537.07 ;
    END
  END dout[36]
  PIN dout[37]
    DIRECTION OUTPUT ;
    USE SIGNAL ;
    PORT
      LAYER metal10 ;
        RECT  191.095 535.07 193.095 537.07 ;
    END
  END dout[37]
  PIN dout[38]
    DIRECTION OUTPUT ;
    USE SIGNAL ;
    PORT
      LAYER metal10 ;
        RECT  199.095 535.07 201.095 537.07 ;
    END
  END dout[38]
  PIN dout[39]
    DIRECTION OUTPUT ;
    USE SIGNAL ;
    PORT
      LAYER metal10 ;
        RECT  207.095 535.07 209.095 537.07 ;
    END
  END dout[39]
  PIN dout[3]
    DIRECTION OUTPUT ;
    USE SIGNAL ;
    PORT
      LAYER metal10 ;
        RECT  47.095 535.07 49.095 537.07 ;
    END
  END dout[3]
  PIN dout[40]
    DIRECTION OUTPUT ;
    USE SIGNAL ;
    PORT
      LAYER metal10 ;
        RECT  215.095 535.07 217.095 537.07 ;
    END
  END dout[40]
  PIN dout[41]
    DIRECTION OUTPUT ;
    USE SIGNAL ;
    PORT
      LAYER metal10 ;
        RECT  223.095 535.07 225.095 537.07 ;
    END
  END dout[41]
  PIN dout[42]
    DIRECTION OUTPUT ;
    USE SIGNAL ;
    PORT
      LAYER metal10 ;
        RECT  231.095 535.07 233.095 537.07 ;
    END
  END dout[42]
  PIN dout[43]
    DIRECTION OUTPUT ;
    USE SIGNAL ;
    PORT
      LAYER metal10 ;
        RECT  239.095 535.07 241.095 537.07 ;
    END
  END dout[43]
  PIN dout[44]
    DIRECTION OUTPUT ;
    USE SIGNAL ;
    PORT
      LAYER metal10 ;
        RECT  247.095 535.07 249.095 537.07 ;
    END
  END dout[44]
  PIN dout[45]
    DIRECTION OUTPUT ;
    USE SIGNAL ;
    PORT
      LAYER metal10 ;
        RECT  255.095 535.07 257.095 537.07 ;
    END
  END dout[45]
  PIN dout[46]
    DIRECTION OUTPUT ;
    USE SIGNAL ;
    PORT
      LAYER metal10 ;
        RECT  263.095 535.07 265.095 537.07 ;
    END
  END dout[46]
  PIN dout[47]
    DIRECTION OUTPUT ;
    USE SIGNAL ;
    PORT
      LAYER metal10 ;
        RECT  271.095 535.07 273.095 537.07 ;
    END
  END dout[47]
  PIN dout[48]
    DIRECTION OUTPUT ;
    USE SIGNAL ;
    PORT
      LAYER metal10 ;
        RECT  151.095 1071.07 153.095 1073.07 ;
    END
  END dout[48]
  PIN dout[49]
    DIRECTION OUTPUT ;
    USE SIGNAL ;
    PORT
      LAYER metal10 ;
        RECT  159.095 1071.07 161.095 1073.07 ;
    END
  END dout[49]
  PIN dout[4]
    DIRECTION OUTPUT ;
    USE SIGNAL ;
    PORT
      LAYER metal10 ;
        RECT  55.095 535.07 57.095 537.07 ;
    END
  END dout[4]
  PIN dout[50]
    DIRECTION OUTPUT ;
    USE SIGNAL ;
    PORT
      LAYER metal10 ;
        RECT  167.095 1071.07 169.095 1073.07 ;
    END
  END dout[50]
  PIN dout[51]
    DIRECTION OUTPUT ;
    USE SIGNAL ;
    PORT
      LAYER metal10 ;
        RECT  175.095 1071.07 177.095 1073.07 ;
    END
  END dout[51]
  PIN dout[52]
    DIRECTION OUTPUT ;
    USE SIGNAL ;
    PORT
      LAYER metal10 ;
        RECT  183.095 1071.07 185.095 1073.07 ;
    END
  END dout[52]
  PIN dout[53]
    DIRECTION OUTPUT ;
    USE SIGNAL ;
    PORT
      LAYER metal10 ;
        RECT  191.095 1071.07 193.095 1073.07 ;
    END
  END dout[53]
  PIN dout[54]
    DIRECTION OUTPUT ;
    USE SIGNAL ;
    PORT
      LAYER metal10 ;
        RECT  199.095 1071.07 201.095 1073.07 ;
    END
  END dout[54]
  PIN dout[55]
    DIRECTION OUTPUT ;
    USE SIGNAL ;
    PORT
      LAYER metal10 ;
        RECT  207.095 1071.07 209.095 1073.07 ;
    END
  END dout[55]
  PIN dout[56]
    DIRECTION OUTPUT ;
    USE SIGNAL ;
    PORT
      LAYER metal10 ;
        RECT  215.095 1071.07 217.095 1073.07 ;
    END
  END dout[56]
  PIN dout[57]
    DIRECTION OUTPUT ;
    USE SIGNAL ;
    PORT
      LAYER metal10 ;
        RECT  223.095 1071.07 225.095 1073.07 ;
    END
  END dout[57]
  PIN dout[58]
    DIRECTION OUTPUT ;
    USE SIGNAL ;
    PORT
      LAYER metal10 ;
        RECT  231.095 1071.07 233.095 1073.07 ;
    END
  END dout[58]
  PIN dout[59]
    DIRECTION OUTPUT ;
    USE SIGNAL ;
    PORT
      LAYER metal10 ;
        RECT  239.095 1071.07 241.095 1073.07 ;
    END
  END dout[59]
  PIN dout[5]
    DIRECTION OUTPUT ;
    USE SIGNAL ;
    PORT
      LAYER metal10 ;
        RECT  63.095 535.07 65.095 537.07 ;
    END
  END dout[5]
  PIN dout[60]
    DIRECTION OUTPUT ;
    USE SIGNAL ;
    PORT
      LAYER metal10 ;
        RECT  247.095 1071.07 249.095 1073.07 ;
    END
  END dout[60]
  PIN dout[61]
    DIRECTION OUTPUT ;
    USE SIGNAL ;
    PORT
      LAYER metal10 ;
        RECT  255.095 1071.07 257.095 1073.07 ;
    END
  END dout[61]
  PIN dout[62]
    DIRECTION OUTPUT ;
    USE SIGNAL ;
    PORT
      LAYER metal10 ;
        RECT  263.095 1071.07 265.095 1073.07 ;
    END
  END dout[62]
  PIN dout[63]
    DIRECTION OUTPUT ;
    USE SIGNAL ;
    PORT
      LAYER metal10 ;
        RECT  271.095 1071.07 273.095 1073.07 ;
    END
  END dout[63]
  PIN dout[64]
    DIRECTION OUTPUT ;
    USE SIGNAL ;
    PORT
      LAYER metal10 ;
        RECT  279.095 535.07 281.095 537.07 ;
    END
  END dout[64]
  PIN dout[65]
    DIRECTION OUTPUT ;
    USE SIGNAL ;
    PORT
      LAYER metal10 ;
        RECT  287.095 535.07 289.095 537.07 ;
    END
  END dout[65]
  PIN dout[66]
    DIRECTION OUTPUT ;
    USE SIGNAL ;
    PORT
      LAYER metal10 ;
        RECT  295.095 535.07 297.095 537.07 ;
    END
  END dout[66]
  PIN dout[67]
    DIRECTION OUTPUT ;
    USE SIGNAL ;
    PORT
      LAYER metal10 ;
        RECT  303.095 535.07 305.095 537.07 ;
    END
  END dout[67]
  PIN dout[68]
    DIRECTION OUTPUT ;
    USE SIGNAL ;
    PORT
      LAYER metal10 ;
        RECT  311.095 535.07 313.095 537.07 ;
    END
  END dout[68]
  PIN dout[69]
    DIRECTION OUTPUT ;
    USE SIGNAL ;
    PORT
      LAYER metal10 ;
        RECT  319.095 535.07 321.095 537.07 ;
    END
  END dout[69]
  PIN dout[6]
    DIRECTION OUTPUT ;
    USE SIGNAL ;
    PORT
      LAYER metal10 ;
        RECT  71.095 535.07 73.095 537.07 ;
    END
  END dout[6]
  PIN dout[70]
    DIRECTION OUTPUT ;
    USE SIGNAL ;
    PORT
      LAYER metal10 ;
        RECT  327.095 535.07 329.095 537.07 ;
    END
  END dout[70]
  PIN dout[71]
    DIRECTION OUTPUT ;
    USE SIGNAL ;
    PORT
      LAYER metal10 ;
        RECT  335.095 535.07 337.095 537.07 ;
    END
  END dout[71]
  PIN dout[72]
    DIRECTION OUTPUT ;
    USE SIGNAL ;
    PORT
      LAYER metal10 ;
        RECT  343.095 535.07 345.095 537.07 ;
    END
  END dout[72]
  PIN dout[73]
    DIRECTION OUTPUT ;
    USE SIGNAL ;
    PORT
      LAYER metal10 ;
        RECT  351.095 535.07 353.095 537.07 ;
    END
  END dout[73]
  PIN dout[74]
    DIRECTION OUTPUT ;
    USE SIGNAL ;
    PORT
      LAYER metal10 ;
        RECT  359.095 535.07 361.095 537.07 ;
    END
  END dout[74]
  PIN dout[75]
    DIRECTION OUTPUT ;
    USE SIGNAL ;
    PORT
      LAYER metal10 ;
        RECT  367.095 535.07 369.095 537.07 ;
    END
  END dout[75]
  PIN dout[76]
    DIRECTION OUTPUT ;
    USE SIGNAL ;
    PORT
      LAYER metal10 ;
        RECT  375.095 535.07 377.095 537.07 ;
    END
  END dout[76]
  PIN dout[77]
    DIRECTION OUTPUT ;
    USE SIGNAL ;
    PORT
      LAYER metal10 ;
        RECT  383.095 535.07 385.095 537.07 ;
    END
  END dout[77]
  PIN dout[78]
    DIRECTION OUTPUT ;
    USE SIGNAL ;
    PORT
      LAYER metal10 ;
        RECT  391.095 535.07 393.095 537.07 ;
    END
  END dout[78]
  PIN dout[79]
    DIRECTION OUTPUT ;
    USE SIGNAL ;
    PORT
      LAYER metal10 ;
        RECT  399.095 535.07 401.095 537.07 ;
    END
  END dout[79]
  PIN dout[7]
    DIRECTION OUTPUT ;
    USE SIGNAL ;
    PORT
      LAYER metal10 ;
        RECT  79.095 535.07 81.095 537.07 ;
    END
  END dout[7]
  PIN dout[80]
    DIRECTION OUTPUT ;
    USE SIGNAL ;
    PORT
      LAYER metal10 ;
        RECT  279.095 1071.07 281.095 1073.07 ;
    END
  END dout[80]
  PIN dout[81]
    DIRECTION OUTPUT ;
    USE SIGNAL ;
    PORT
      LAYER metal10 ;
        RECT  287.095 1071.07 289.095 1073.07 ;
    END
  END dout[81]
  PIN dout[82]
    DIRECTION OUTPUT ;
    USE SIGNAL ;
    PORT
      LAYER metal10 ;
        RECT  295.095 1071.07 297.095 1073.07 ;
    END
  END dout[82]
  PIN dout[83]
    DIRECTION OUTPUT ;
    USE SIGNAL ;
    PORT
      LAYER metal10 ;
        RECT  303.095 1071.07 305.095 1073.07 ;
    END
  END dout[83]
  PIN dout[84]
    DIRECTION OUTPUT ;
    USE SIGNAL ;
    PORT
      LAYER metal10 ;
        RECT  311.095 1071.07 313.095 1073.07 ;
    END
  END dout[84]
  PIN dout[85]
    DIRECTION OUTPUT ;
    USE SIGNAL ;
    PORT
      LAYER metal10 ;
        RECT  319.095 1071.07 321.095 1073.07 ;
    END
  END dout[85]
  PIN dout[86]
    DIRECTION OUTPUT ;
    USE SIGNAL ;
    PORT
      LAYER metal10 ;
        RECT  327.095 1071.07 329.095 1073.07 ;
    END
  END dout[86]
  PIN dout[87]
    DIRECTION OUTPUT ;
    USE SIGNAL ;
    PORT
      LAYER metal10 ;
        RECT  335.095 1071.07 337.095 1073.07 ;
    END
  END dout[87]
  PIN dout[88]
    DIRECTION OUTPUT ;
    USE SIGNAL ;
    PORT
      LAYER metal10 ;
        RECT  343.095 1071.07 345.095 1073.07 ;
    END
  END dout[88]
  PIN dout[89]
    DIRECTION OUTPUT ;
    USE SIGNAL ;
    PORT
      LAYER metal10 ;
        RECT  351.095 1071.07 353.095 1073.07 ;
    END
  END dout[89]
  PIN dout[8]
    DIRECTION OUTPUT ;
    USE SIGNAL ;
    PORT
      LAYER metal10 ;
        RECT  87.095 535.07 89.095 537.07 ;
    END
  END dout[8]
  PIN dout[90]
    DIRECTION OUTPUT ;
    USE SIGNAL ;
    PORT
      LAYER metal10 ;
        RECT  359.095 1071.07 361.095 1073.07 ;
    END
  END dout[90]
  PIN dout[91]
    DIRECTION OUTPUT ;
    USE SIGNAL ;
    PORT
      LAYER metal10 ;
        RECT  367.095 1071.07 369.095 1073.07 ;
    END
  END dout[91]
  PIN dout[92]
    DIRECTION OUTPUT ;
    USE SIGNAL ;
    PORT
      LAYER metal10 ;
        RECT  375.095 1071.07 377.095 1073.07 ;
    END
  END dout[92]
  PIN dout[93]
    DIRECTION OUTPUT ;
    USE SIGNAL ;
    PORT
      LAYER metal10 ;
        RECT  383.095 1071.07 385.095 1073.07 ;
    END
  END dout[93]
  PIN dout[94]
    DIRECTION OUTPUT ;
    USE SIGNAL ;
    PORT
      LAYER metal10 ;
        RECT  391.095 1071.07 393.095 1073.07 ;
    END
  END dout[94]
  PIN dout[95]
    DIRECTION OUTPUT ;
    USE SIGNAL ;
    PORT
      LAYER metal10 ;
        RECT  399.095 1071.07 401.095 1073.07 ;
    END
  END dout[95]
  PIN dout[96]
    DIRECTION OUTPUT ;
    USE SIGNAL ;
    PORT
      LAYER metal10 ;
        RECT  407.095 535.07 409.095 537.07 ;
    END
  END dout[96]
  PIN dout[97]
    DIRECTION OUTPUT ;
    USE SIGNAL ;
    PORT
      LAYER metal10 ;
        RECT  415.095 535.07 417.095 537.07 ;
    END
  END dout[97]
  PIN dout[98]
    DIRECTION OUTPUT ;
    USE SIGNAL ;
    PORT
      LAYER metal10 ;
        RECT  423.095 535.07 425.095 537.07 ;
    END
  END dout[98]
  PIN dout[99]
    DIRECTION OUTPUT ;
    USE SIGNAL ;
    PORT
      LAYER metal10 ;
        RECT  431.095 535.07 433.095 537.07 ;
    END
  END dout[99]
  PIN dout[9]
    DIRECTION OUTPUT ;
    USE SIGNAL ;
    PORT
      LAYER metal10 ;
        RECT  95.095 535.07 97.095 537.07 ;
    END
  END dout[9]
  PIN ready
    DIRECTION OUTPUT ;
    USE SIGNAL ;
    PORT
      LAYER metal10 ;
        RECT  535.095 535.07 537.095 537.07 ;
    END
  END ready
  PIN req
    DIRECTION INPUT ;
    USE SIGNAL ;
    PORT
      LAYER metal10 ;
        RECT  535.095 623.07 537.095 625.07 ;
    END
  END req
  PIN reset
    DIRECTION INPUT ;
    USE SIGNAL ;
    PORT
      LAYER metal10 ;
        RECT  1071.095 551.07 1073.095 553.07 ;
    END
  END reset
  PIN take
    DIRECTION INPUT ;
    USE SIGNAL ;
    PORT
      LAYER metal10 ;
        RECT  535.095 631.07 537.095 633.07 ;
    END
  END take
  PIN valid
    DIRECTION OUTPUT ;
    USE SIGNAL ;
    PORT
      LAYER metal10 ;
        RECT  535.095 1071.07 537.095 1073.07 ;
    END
  END valid
  PIN wr
    DIRECTION INPUT ;
    USE SIGNAL ;
    PORT
      LAYER metal10 ;
        RECT  1071.095 559.07 1073.095 561.07 ;
    END
  END wr
  PIN VDD
    DIRECTION INOUT ;
    USE POWER ;
    PORT
      LAYER metal7 ;
        RECT  20.14 1567.3 1589.92 1568.7 ;
        RECT  20.14 1537.3 1589.92 1538.7 ;
        RECT  20.14 1507.3 1589.92 1508.7 ;
        RECT  20.14 1477.3 1589.92 1478.7 ;
        RECT  20.14 1447.3 1589.92 1448.7 ;
        RECT  20.14 1417.3 1589.92 1418.7 ;
        RECT  20.14 1387.3 1589.92 1388.7 ;
        RECT  20.14 1357.3 1589.92 1358.7 ;
        RECT  20.14 1327.3 1589.92 1328.7 ;
        RECT  20.14 1297.3 1589.92 1298.7 ;
        RECT  20.14 1267.3 1589.92 1268.7 ;
        RECT  20.14 1237.3 1589.92 1238.7 ;
        RECT  20.14 1207.3 1589.92 1208.7 ;
        RECT  20.14 1177.3 1589.92 1178.7 ;
        RECT  20.14 1147.3 1589.92 1148.7 ;
        RECT  20.14 1117.3 1589.92 1118.7 ;
        RECT  20.14 1087.3 1589.92 1088.7 ;
        RECT  20.14 1057.3 1589.92 1058.7 ;
        RECT  20.14 1027.3 1589.92 1028.7 ;
        RECT  20.14 997.3 1589.92 998.7 ;
        RECT  20.14 967.3 1589.92 968.7 ;
        RECT  20.14 937.3 1589.92 938.7 ;
        RECT  20.14 907.3 1589.92 908.7 ;
        RECT  20.14 877.3 1589.92 878.7 ;
        RECT  20.14 847.3 1589.92 848.7 ;
        RECT  20.14 817.3 1589.92 818.7 ;
        RECT  20.14 787.3 1589.92 788.7 ;
        RECT  20.14 757.3 1589.92 758.7 ;
        RECT  20.14 727.3 1589.92 728.7 ;
        RECT  20.14 697.3 1589.92 698.7 ;
        RECT  20.14 667.3 1589.92 668.7 ;
        RECT  20.14 637.3 1589.92 638.7 ;
        RECT  20.14 607.3 1589.92 608.7 ;
        RECT  20.14 577.3 1589.92 578.7 ;
        RECT  20.14 547.3 1589.92 548.7 ;
        RECT  20.14 517.3 1589.92 518.7 ;
        RECT  20.14 487.3 1589.92 488.7 ;
        RECT  20.14 457.3 1589.92 458.7 ;
        RECT  20.14 427.3 1589.92 428.7 ;
        RECT  20.14 397.3 1589.92 398.7 ;
        RECT  20.14 367.3 1589.92 368.7 ;
        RECT  20.14 337.3 1589.92 338.7 ;
        RECT  20.14 307.3 1589.92 308.7 ;
        RECT  20.14 277.3 1589.92 278.7 ;
        RECT  20.14 247.3 1589.92 248.7 ;
        RECT  20.14 217.3 1589.92 218.7 ;
        RECT  20.14 187.3 1589.92 188.7 ;
        RECT  20.14 157.3 1589.92 158.7 ;
        RECT  20.14 127.3 1589.92 128.7 ;
        RECT  20.14 97.3 1589.92 98.7 ;
        RECT  20.14 67.3 1589.92 68.7 ;
        RECT  20.14 37.3 1589.92 38.7 ;
    END
  END VDD
  PIN VSS
    DIRECTION INOUT ;
    USE GROUND ;
    PORT
      LAYER metal7 ;
        RECT  20.14 1582.3 1589.92 1583.7 ;
        RECT  20.14 1552.3 1589.92 1553.7 ;
        RECT  20.14 1522.3 1589.92 1523.7 ;
        RECT  20.14 1492.3 1589.92 1493.7 ;
        RECT  20.14 1462.3 1589.92 1463.7 ;
        RECT  20.14 1432.3 1589.92 1433.7 ;
        RECT  20.14 1402.3 1589.92 1403.7 ;
        RECT  20.14 1372.3 1589.92 1373.7 ;
        RECT  20.14 1342.3 1589.92 1343.7 ;
        RECT  20.14 1312.3 1589.92 1313.7 ;
        RECT  20.14 1282.3 1589.92 1283.7 ;
        RECT  20.14 1252.3 1589.92 1253.7 ;
        RECT  20.14 1222.3 1589.92 1223.7 ;
        RECT  20.14 1192.3 1589.92 1193.7 ;
        RECT  20.14 1162.3 1589.92 1163.7 ;
        RECT  20.14 1132.3 1589.92 1133.7 ;
        RECT  20.14 1102.3 1589.92 1103.7 ;
        RECT  20.14 1072.3 1589.92 1073.7 ;
        RECT  20.14 1042.3 1589.92 1043.7 ;
        RECT  20.14 1012.3 1589.92 1013.7 ;
        RECT  20.14 982.3 1589.92 983.7 ;
        RECT  20.14 952.3 1589.92 953.7 ;
        RECT  20.14 922.3 1589.92 923.7 ;
        RECT  20.14 892.3 1589.92 893.7 ;
        RECT  20.14 862.3 1589.92 863.7 ;
        RECT  20.14 832.3 1589.92 833.7 ;
        RECT  20.14 802.3 1589.92 803.7 ;
        RECT  20.14 772.3 1589.92 773.7 ;
        RECT  20.14 742.3 1589.92 743.7 ;
        RECT  20.14 712.3 1589.92 713.7 ;
        RECT  20.14 682.3 1589.92 683.7 ;
        RECT  20.14 652.3 1589.92 653.7 ;
        RECT  20.14 622.3 1589.92 623.7 ;
        RECT  20.14 592.3 1589.92 593.7 ;
        RECT  20.14 562.3 1589.92 563.7 ;
        RECT  20.14 532.3 1589.92 533.7 ;
        RECT  20.14 502.3 1589.92 503.7 ;
        RECT  20.14 472.3 1589.92 473.7 ;
        RECT  20.14 442.3 1589.92 443.7 ;
        RECT  20.14 412.3 1589.92 413.7 ;
        RECT  20.14 382.3 1589.92 383.7 ;
        RECT  20.14 352.3 1589.92 353.7 ;
        RECT  20.14 322.3 1589.92 323.7 ;
        RECT  20.14 292.3 1589.92 293.7 ;
        RECT  20.14 262.3 1589.92 263.7 ;
        RECT  20.14 232.3 1589.92 233.7 ;
        RECT  20.14 202.3 1589.92 203.7 ;
        RECT  20.14 172.3 1589.92 173.7 ;
        RECT  20.14 142.3 1589.92 143.7 ;
        RECT  20.14 112.3 1589.92 113.7 ;
        RECT  20.14 82.3 1589.92 83.7 ;
        RECT  20.14 52.3 1589.92 53.7 ;
        RECT  20.14 22.3 1589.92 23.7 ;
    END
  END VSS
  OBS
    LAYER metal1 ;
     RECT  20.14 20.915 1589.92 1589.42 ;
    LAYER metal2 ;
     RECT  20.14 20.915 1589.92 1589.42 ;
    LAYER metal3 ;
     RECT  20.14 20.915 1589.92 1589.42 ;
    LAYER metal4 ;
     RECT  20.14 20.915 1589.92 1589.42 ;
    LAYER metal5 ;
     RECT  20.14 20.915 1589.92 1589.42 ;
    LAYER metal6 ;
     RECT  20.14 20.915 1589.92 1589.42 ;
    LAYER metal7 ;
     RECT  20.14 20.915 1589.92 1589.42 ;
    LAYER metal8 ;
     RECT  20.14 20.915 1589.92 1589.42 ;
    LAYER metal9 ;
     RECT  20.14 20.915 1589.92 1589.42 ;
    LAYER metal10 ;
     RECT  20.14 20.915 1589.92 1589.42 ;
  END
END block_v1_s16k
END LIBRARY
